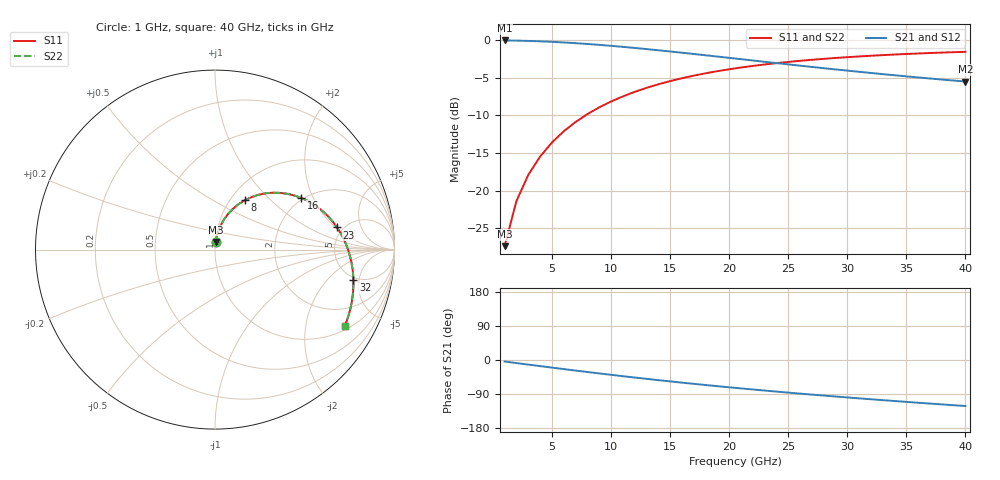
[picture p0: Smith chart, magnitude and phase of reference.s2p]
! circuitRF F0 spike reference -- case A, openEMS, PEC wire of true radius 12.7 um, dw 4.2333 um
! openEMS probes -> S by postproc.py (own time column per probe); port 1 excited only;
! S22 = S11 and S12 = S21 by the mirror symmetry of the geometry (not a second run)
# GHz S RI R 50
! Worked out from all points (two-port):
!   40 points, 1 GHz to 40 GHz, reference 50 ohm
!   highest |S21| = -0.01 dB at 1 GHz (marker M1); lowest = -5.5 dB at 40 GHz (marker M2)
!   |S21| within 3 dB of the highest: start of sweep to 23.92 GHz
!   lowest |S11| = -27.4 dB at 1 GHz (marker M3), VSWR 1.09, Z = 50.1 + j4.27 ohm
!   |S11| at or under -10 dB: start of sweep to 7.835 GHz
!   |S22| runs from -27.4 to -1.5 dB; largest |S21 - S12| = 0
!   S11 on the Smith chart (normalised r, x): 1 GHz: 1.00, +0.09; 8 GHz: 1.16, +0.72; 16 GHz: 1.94, +1.63; 23 GHz: 4.44, +2.10; 32 GHz: 4.60, -4.19; 40 GHz: 1.16, -3.31
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1  0.00311 0.0425  0.9964 -0.0704  0.9964 -0.0704  0.00311 0.0425
2  0.0119 0.0841  0.9863 -0.14  0.9863 -0.14  0.0119 0.0841
3  0.0263 0.1242  0.9698 -0.2079  0.9698 -0.2079  0.0263 0.1242
4  0.0461 0.1618  0.9471 -0.2732  0.9471 -0.2732  0.0461 0.1618
5  0.0706 0.1963  0.9188 -0.3353  0.9188 -0.3353  0.0706 0.1963
6  0.0995 0.2271  0.8853 -0.3935  0.8853 -0.3935  0.0995 0.2271
7  0.132 0.2537  0.8474 -0.4474  0.8474 -0.4474  0.132 0.2537
8  0.1674 0.2758  0.8058 -0.4965  0.8058 -0.4965  0.1674 0.2758
9  0.205 0.2932  0.7612 -0.5406  0.7612 -0.5406  0.205 0.2932
11  0.2843 0.3137  0.6658 -0.6138  0.6658 -0.6138  0.2843 0.3137
14  0.4042 0.3105  0.5163 -0.6872  0.5163 -0.6872  0.4042 0.3105
16  0.4794 0.2884  0.4181 -0.7145  0.4181 -0.7145  0.4794 0.2884
18  0.5478 0.253  0.3241 -0.7271  0.3241 -0.7271  0.5478 0.253
21  0.6341 0.1809  0.1949 -0.7239  0.1949 -0.7239  0.6341 0.1809
23  0.6798 0.1237  0.1176 -0.7106  0.1176 -0.7106  0.6798 0.1237
25  0.7158 0.0616  0.0478 -0.6905  0.0478 -0.6905  0.7158 0.0616
27  0.7424 -0.00364  -0.0149 -0.6655  -0.0149 -0.6655  0.7424 -0.00364
29  0.7601 -0.0704  -0.0706 -0.637  -0.0706 -0.637  0.7601 -0.0704
32  0.7712 -0.1712  -0.1425 -0.5897  -0.1425 -0.5897  0.7712 -0.1712
34  0.7691 -0.2374  -0.1834 -0.5564  -0.1834 -0.5564  0.7691 -0.2374
37  0.7533 -0.3337  -0.2353 -0.5053  -0.2353 -0.5053  0.7533 -0.3337
40  0.7238 -0.4243  -0.2773 -0.4541  -0.2773 -0.4541  0.7238 -0.4243
